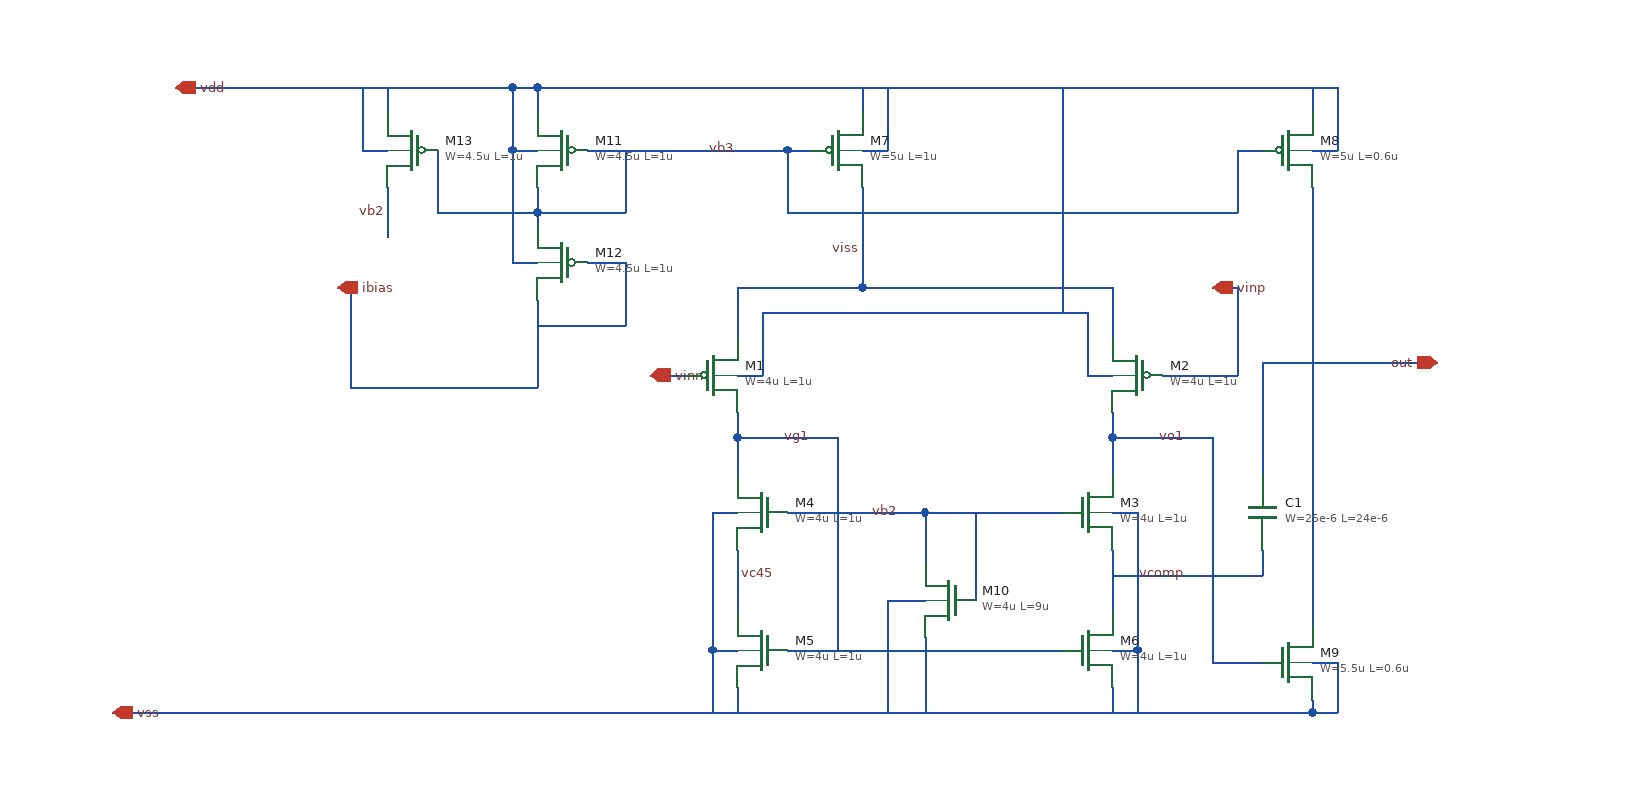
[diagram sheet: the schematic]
v {xschem version=3.4.7 file_version=1.2}
G {}
K {}
V {}
S {}
E {}
N 570 -470 570 -430 {lab=viss}
N 870 -470 870 -430 {lab=viss}
N 1030 -580 1050 -580 {lab=vdd}
N 1050 -630 1050 -580 {lab=vdd}
N 410 -630 1050 -630 {lab=vdd}
N 1030 -630 1030 -610 {lab=vdd}
N 1030 -550 1030 -340 {lab=out}
N 1030 -410 1130 -410 {lab=out}
N 410 -130 1030 -130 {lab=vss}
N 1030 -130 1050 -130 {lab=vss}
N 870 -180 890 -180 {lab=vss}
N 890 -180 890 -130 {lab=vss}
N 870 -150 870 -130 {lab=vss}
N 710 -180 830 -180 {lab=vg1}
N 570 -150 570 -130 {lab=vss}
N 570 -250 570 -210 {lab=vc45}
N 650 -250 650 -180 {lab=vg1}
N 550 -180 570 -180 {lab=vss}
N 550 -180 550 -130 {lab=vss}
N 570 -400 590 -400 {lab=vdd}
N 590 -450 590 -400 {lab=vdd}
N 690 -450 850 -450 {lab=vdd}
N 850 -450 850 -400 {lab=vdd}
N 850 -400 870 -400 {lab=vdd}
N 570 -370 570 -350 {lab=vg1}
N 870 -370 870 -350 {lab=vo1}
N 670 -550 670 -470 {lab=viss}
N 670 -630 670 -610 {lab=vdd}
N 670 -550 670 -470 {lab=viss}
N 670 -630 670 -610 {lab=vdd}
N 670 -580 690 -580 {lab=vdd}
N 690 -630 690 -580 {lab=vdd}
N 970 -580 990 -580 {lab=vb3}
N 970 -580 970 -530 {lab=vb3}
N 710 -530 970 -530 {lab=vb3}
N 610 -580 610 -530 {lab=vb3}
N 610 -580 630 -580 {lab=vb3}
N 450 -580 610 -580 {lab=vb3}
N 390 -580 410 -580 {lab=vdd}
N 410 -630 410 -610 {lab=vdd}
N 390 -630 390 -580 {lab=vdd}
N 410 -550 410 -530 {lab=vb3}
N 1030 -170 1050 -170 {lab=vss}
N 1030 -260 1030 -200 {lab=out}
N 910 -400 930 -400 {lab=vinp}
N 930 -400 970 -400 {lab=vinp}
N 970 -470 970 -400 {lab=vinp}
N 950 -470 970 -470 {lab=vinp}
N 670 -470 870 -470 {lab=viss}
N 830 -630 830 -450 {lab=vdd}
N 590 -450 690 -450 {lab=vdd}
N 570 -470 670 -470 {lab=viss}
N 610 -530 710 -530 {lab=vb3}
N 610 -180 710 -180 {lab=vg1}
N 390 -630 410 -630 {lab=vdd}
N 310 -130 410 -130 {lab=vss}
N 310 -630 390 -630 {lab=vdd}
N 210 -130 310 -130 {lab=vss}
N 120 -130 130 -130 {lab=vss}
N 70 -130 210 -130 {lab=vss}
N 250 -470 260 -470 {lab=ibias}
N 260 -470 260 -400 {lab=ibias}
N 680 -290 720 -290 {lab=vb2}
N 500 -400 530 -400 {lab=vinn}
N 410 -530 410 -520 {lab=vb3}
N 480 -580 480 -530 {lab=vb3}
N 720 -290 720 -250 {lab=vb2}
N 970 -170 990 -170 {lab=vo1}
N 450 -490 480 -490 {lab=ibias}
N 480 -490 480 -440 {lab=ibias}
N 410 -440 480 -440 {lab=ibias}
N 410 -460 410 -400 {lab=ibias}
N 410 -530 480 -530 {lab=vb3}
N 390 -490 410 -490 {lab=vdd}
N 390 -580 390 -490 {lab=vdd}
N 720 -290 830 -290 {lab=vb2}
N 610 -290 680 -290 {lab=vb2}
N 870 -350 870 -330 {lab=vo1}
N 570 -260 570 -250 {lab=vc45}
N 570 -350 570 -320 {lab=vg1}
N 870 -330 870 -320 {lab=vo1}
N 950 -270 950 -170 {lab=vo1}
N 870 -260 870 -220 {lab=vcomp}
N 870 -220 870 -210 {lab=vcomp}
N 1030 -140 1030 -130 {lab=vss}
N 1030 -340 1030 -260 {lab=out}
N 1050 -170 1050 -130 {lab=vss}
N 950 -170 970 -170 {lab=vo1}
N 950 -350 950 -270 {lab=vo1}
N 550 -290 570 -290 {lab=vss}
N 550 -290 550 -180 {lab=vss}
N 890 -290 890 -180 {lab=vss}
N 720 -190 720 -130 {lab=vss}
N 690 -220 720 -220 {lab=vss}
N 690 -220 690 -130 {lab=vss}
N 760 -290 760 -220 {lab=vb2}
N 120 -630 310 -630 {lab=vdd}
N 270 -630 270 -580 {lab=vdd}
N 290 -630 290 -620 {lab=vdd}
N 270 -580 290 -580 {lab=vdd}
N 290 -620 290 -610 {lab=vdd}
N 330 -580 330 -530 {lab=vb3}
N 330 -530 410 -530 {lab=vb3}
N 290 -550 290 -510 {lab=vb2}
N 650 -350 650 -250 {lab=vg1}
N 570 -350 650 -350 {lab=vg1}
N 870 -290 890 -290 {lab=vss}
N 870 -240 990 -240 {lab=vcomp}
N 990 -260 990 -240 {lab=vcomp}
N 990 -410 990 -320 {lab=out}
N 870 -350 950 -350 {lab=vo1}
N 990 -410 1030 -410 {lab=out}
N 260 -400 260 -390 {lab=ibias}
N 410 -400 410 -390 {lab=ibias}
N 260 -390 410 -390 {lab=ibias}
C {title.sym} 160 -40 0 0 {name=l1 author="X.J. Lee"}
C {opin.sym} 1130 -410 2 1 {name=p1 lab=out}
C {ipin.sym} 120 -630 2 1 {name=p2 lab=vdd}
C {ipin.sym} 70 -130 2 1 {name=p3 lab=vss}
C {ipin.sym} 500 -400 2 1 {name=p4 lab=vinn}
C {ipin.sym} 250 -470 2 1 {name=p5 lab=ibias}
C {ipin.sym} 950 -470 2 1 {name=p6 lab=vinp}
C {lab_wire.sym} 630 -350 2 1 {name=p7 sig_type=std_logic lab=vg1}
C {lab_wire.sym} 670 -500 2 1 {name=p9 sig_type=std_logic lab=viss}
C {lab_wire.sym} 700 -290 2 1 {name=p11 sig_type=std_logic lab=vb2}
C {symbols/pfet_03v3.sym} 650 -580 0 0 {name=M7
L=1u
W=5u
nf=1
m=5
ad="'int((nf+1)/2) * W/nf * 0.18u'"
pd="'2*int((nf+1)/2) * (W/nf + 0.18u)'"
as="'int((nf+2)/2) * W/nf * 0.18u'"
ps="'2*int((nf+2)/2) * (W/nf + 0.18u)'"
nrd="'0.18u / W'" nrs="'0.18u / W'"
sa=0 sb=0 sd=0
model=pfet_03v3
spiceprefix=X
}
C {symbols/pfet_03v3.sym} 1010 -580 0 0 {name=M8
L=0.6u
W=5u
nf=1
m=6
ad="'int((nf+1)/2) * W/nf * 0.18u'"
pd="'2*int((nf+1)/2) * (W/nf + 0.18u)'"
as="'int((nf+2)/2) * W/nf * 0.18u'"
ps="'2*int((nf+2)/2) * (W/nf + 0.18u)'"
nrd="'0.18u / W'" nrs="'0.18u / W'"
sa=0 sb=0 sd=0
model=pfet_03v3
spiceprefix=X
}
C {symbols/pfet_03v3.sym} 430 -580 0 1 {name=M11
L=1u
W=4.5u
nf=1
m=2
ad="'int((nf+1)/2) * W/nf * 0.18u'"
pd="'2*int((nf+1)/2) * (W/nf + 0.18u)'"
as="'int((nf+2)/2) * W/nf * 0.18u'"
ps="'2*int((nf+2)/2) * (W/nf + 0.18u)'"
nrd="'0.18u / W'" nrs="'0.18u / W'"
sa=0 sb=0 sd=0
model=pfet_03v3
spiceprefix=X
}
C {symbols/pfet_03v3.sym} 430 -490 0 1 {name=M12
L=1u
W=4.5u
nf=1
m=2
ad="'int((nf+1)/2) * W/nf * 0.18u'"
pd="'2*int((nf+1)/2) * (W/nf + 0.18u)'"
as="'int((nf+2)/2) * W/nf * 0.18u'"
ps="'2*int((nf+2)/2) * (W/nf + 0.18u)'"
nrd="'0.18u / W'" nrs="'0.18u / W'"
sa=0 sb=0 sd=0
model=pfet_03v3
spiceprefix=X
}
C {symbols/pfet_03v3.sym} 550 -400 0 0 {name=M1
L=1u
W=4u
nf=1
m=4
ad="'int((nf+1)/2) * W/nf * 0.18u'"
pd="'2*int((nf+1)/2) * (W/nf + 0.18u)'"
as="'int((nf+2)/2) * W/nf * 0.18u'"
ps="'2*int((nf+2)/2) * (W/nf + 0.18u)'"
nrd="'0.18u / W'" nrs="'0.18u / W'"
sa=0 sb=0 sd=0
model=pfet_03v3
spiceprefix=X
}
C {symbols/pfet_03v3.sym} 890 -400 0 1 {name=M2
L=1u
W=4u
nf=1
m=4
ad="'int((nf+1)/2) * W/nf * 0.18u'"
pd="'2*int((nf+1)/2) * (W/nf + 0.18u)'"
as="'int((nf+2)/2) * W/nf * 0.18u'"
ps="'2*int((nf+2)/2) * (W/nf + 0.18u)'"
nrd="'0.18u / W'" nrs="'0.18u / W'"
sa=0 sb=0 sd=0
model=pfet_03v3
spiceprefix=X
}
C {symbols/nfet_03v3.sym} 590 -180 0 1 {name=M5
L=1u
W=4u
nf=1
m=2
ad="'int((nf+1)/2) * W/nf * 0.18u'"
pd="'2*int((nf+1)/2) * (W/nf + 0.18u)'"
as="'int((nf+2)/2) * W/nf * 0.18u'"
ps="'2*int((nf+2)/2) * (W/nf + 0.18u)'"
nrd="'0.18u / W'" nrs="'0.18u / W'"
sa=0 sb=0 sd=0
model=nfet_03v3
spiceprefix=X
}
C {symbols/nfet_03v3.sym} 850 -180 0 0 {name=M6
L=1u
W=4u
nf=1
m=2
ad="'int((nf+1)/2) * W/nf * 0.18u'"
pd="'2*int((nf+1)/2) * (W/nf + 0.18u)'"
as="'int((nf+2)/2) * W/nf * 0.18u'"
ps="'2*int((nf+2)/2) * (W/nf + 0.18u)'"
nrd="'0.18u / W'" nrs="'0.18u / W'"
sa=0 sb=0 sd=0
model=nfet_03v3
spiceprefix=X
}
C {symbols/nfet_03v3.sym} 1010 -170 0 0 {name=M9
L=0.6u
W=5.5u
nf=1
m=4
ad="'int((nf+1)/2) * W/nf * 0.18u'"
pd="'2*int((nf+1)/2) * (W/nf + 0.18u)'"
as="'int((nf+2)/2) * W/nf * 0.18u'"
ps="'2*int((nf+2)/2) * (W/nf + 0.18u)'"
nrd="'0.18u / W'" nrs="'0.18u / W'"
sa=0 sb=0 sd=0
model=nfet_03v3
spiceprefix=X
}
C {symbols/nfet_03v3.sym} 850 -290 0 0 {name=M3
L=1u
W=4u
nf=1
m=2
ad="'int((nf+1)/2) * W/nf * 0.18u'"
pd="'2*int((nf+1)/2) * (W/nf + 0.18u)'"
as="'int((nf+2)/2) * W/nf * 0.18u'"
ps="'2*int((nf+2)/2) * (W/nf + 0.18u)'"
nrd="'0.18u / W'" nrs="'0.18u / W'"
sa=0 sb=0 sd=0
model=nfet_03v3
spiceprefix=X
}
C {symbols/nfet_03v3.sym} 590 -290 0 1 {name=M4
L=1u
W=4u
nf=1
m=2
ad="'int((nf+1)/2) * W/nf * 0.18u'"
pd="'2*int((nf+1)/2) * (W/nf + 0.18u)'"
as="'int((nf+2)/2) * W/nf * 0.18u'"
ps="'2*int((nf+2)/2) * (W/nf + 0.18u)'"
nrd="'0.18u / W'" nrs="'0.18u / W'"
sa=0 sb=0 sd=0
model=nfet_03v3
spiceprefix=X
}
C {symbols/nfet_03v3.sym} 740 -220 0 1 {name=M10
L=9u
W=4u
nf=1
m=1
ad="'int((nf+1)/2) * W/nf * 0.18u'"
pd="'2*int((nf+1)/2) * (W/nf + 0.18u)'"
as="'int((nf+2)/2) * W/nf * 0.18u'"
ps="'2*int((nf+2)/2) * (W/nf + 0.18u)'"
nrd="'0.18u / W'" nrs="'0.18u / W'"
sa=0 sb=0 sd=0
model=nfet_03v3
spiceprefix=X
}
C {symbols/pfet_03v3.sym} 310 -580 0 1 {name=M13
L=1u
W=4.5u
nf=1
m=1
ad="'int((nf+1)/2) * W/nf * 0.18u'"
pd="'2*int((nf+1)/2) * (W/nf + 0.18u)'"
as="'int((nf+2)/2) * W/nf * 0.18u'"
ps="'2*int((nf+2)/2) * (W/nf + 0.18u)'"
nrd="'0.18u / W'" nrs="'0.18u / W'"
sa=0 sb=0 sd=0
model=pfet_03v3
spiceprefix=X
}
C {lab_wire.sym} 290 -530 2 1 {name=p8 sig_type=std_logic lab=vb2}
C {symbols/cap_mim_2f0fF.sym} 990 -290 0 0 {name=C1
W=25e-6
L=24e-6
model=cap_mim_2f0fF
spiceprefix=X
m=1}
C {lab_wire.sym} 570 -580 2 1 {name=p12 sig_type=std_logic lab=vb3}
C {lab_wire.sym} 930 -350 2 1 {name=p13 sig_type=std_logic lab=vo1}
C {lab_wire.sym} 930 -240 2 1 {name=p14 sig_type=std_logic lab=vcomp}
C {lab_wire.sym} 570 -240 2 0 {name=p15 sig_type=std_logic lab=vc45}
